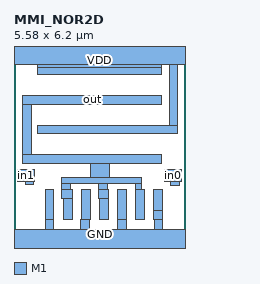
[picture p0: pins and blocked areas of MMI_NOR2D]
MACRO MMI_NOR2D
	CLASS CORE ;
	FOREIGN MMI_NOR2D 0 0 ;
	SIZE 5.58 BY 6.2 ;
	SYMMETRY X Y ;
	SITE CORE1 ;
	PIN out
		DIRECTION output ;
		USE SIGNAL ;
		PORT
			LAYER M1 ;
			RECT 0.285 4.495 4.81 4.775 ;
			LAYER M1 ;
			RECT 0.285 2.845 0.57 4.495 ;
			LAYER M1 ;
			RECT 0.285 2.565 4.81 2.845 ;
			LAYER M1 ;
			RECT 2.51 2.11 3.11 2.565 ;
			LAYER M1 ;
			RECT 1.565 1.915 4.17 2.11 ;
			LAYER M1 ;
			RECT 1.565 1.705 1.85 1.915 ;
			LAYER M1 ;
			RECT 2.77 1.705 3.055 1.915 ;
			LAYER M1 ;
			RECT 3.98 1.705 4.17 1.915 ;
			LAYER M1 ;
			RECT 1.565 1.425 1.895 1.705 ;
			LAYER M1 ;
			RECT 2.77 1.425 3.075 1.705 ;
			LAYER M1 ;
			RECT 1.615 0.75 1.895 1.425 ;
			LAYER M1 ;
			RECT 2.795 0.75 3.075 1.425 ;
			LAYER M1 ;
			RECT 3.975 0.75 4.255 1.705 ;
		END
		AntennaDiffArea 4.8012 ;
	END out
	PIN in1
		DIRECTION input ;
		USE SIGNAL ;
		PORT
			LAYER M1 ;
			RECT 0.12 1.98 0.655 2.36 ;
			LAYER M1 ;
			RECT 0.37 1.865 0.65 1.98 ;
		END
		AntennaGateArea 2.3085 ;
	END in1
	PIN GND
		DIRECTION inout ;
		USE GROUND ;
		PORT
			LAYER M1 ;
			RECT 1.025 0.75 1.305 1.705 ;
			LAYER M1 ;
			RECT 2.205 0.75 2.485 1.705 ;
			LAYER M1 ;
			RECT 3.385 0.75 3.665 1.705 ;
			LAYER M1 ;
			RECT 4.565 1.035 4.845 1.705 ;
			LAYER M1 ;
			RECT 4.565 0.75 4.855 1.035 ;
			LAYER M1 ;
			RECT 1.015 0.42 1.3 0.75 ;
			LAYER M1 ;
			RECT 2.185 0.42 2.47 0.75 ;
			LAYER M1 ;
			RECT 3.39 0.42 3.675 0.75 ;
			LAYER M1 ;
			RECT 4.57 0.42 4.855 0.75 ;
			LAYER M1 ;
			RECT 0 -0.42 5.58 0.42 ;
		END
	END GND
	PIN VDD
		DIRECTION inout ;
		USE POWER ;
		PORT
			LAYER M1 ;
			RECT 0 5.78 5.58 6.62 ;
			LAYER M1 ;
			RECT 0.77 5.705 4.81 5.78 ;
			LAYER M1 ;
			RECT 0.775 5.46 4.81 5.705 ;
			LAYER M1 ;
			RECT 5.065 3.805 5.35 5.78 ;
			LAYER M1 ;
			RECT 0.775 3.525 5.35 3.805 ;
		END
	END VDD
	PIN in0
		DIRECTION input ;
		USE SIGNAL ;
		PORT
			LAYER M1 ;
			RECT 4.9 1.98 5.46 2.36 ;
			LAYER M1 ;
			RECT 5.12 1.86 5.4 1.98 ;
		END
		AntennaGateArea 2.3085 ;
	END in0
	OBS
	END
END MMI_NOR2D
